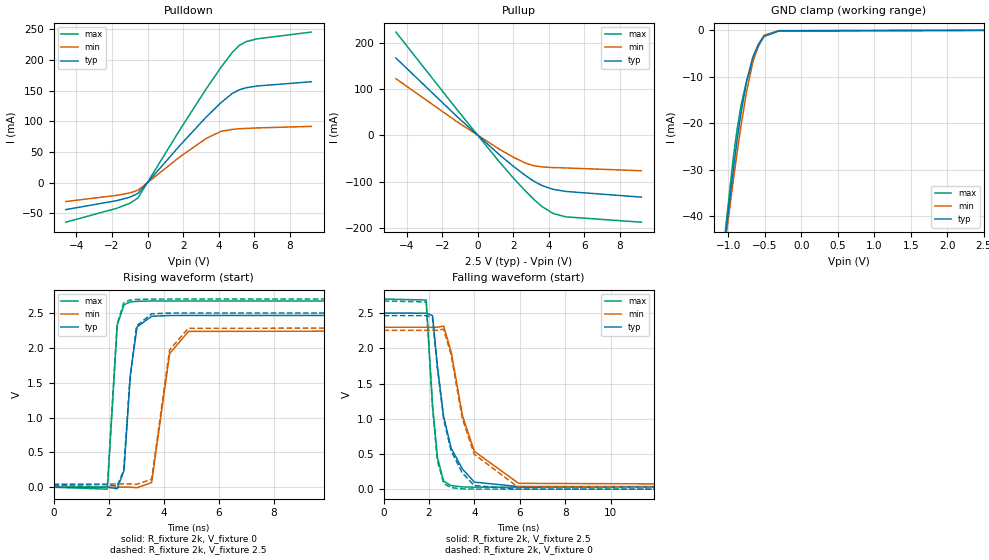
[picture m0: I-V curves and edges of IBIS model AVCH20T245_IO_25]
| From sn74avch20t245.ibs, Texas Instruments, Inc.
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[Model]   AVCH20T245_IO_25
Model_type  I/O
Vinl=0.7
Vinh=1.6
Enable   Active-Low
Vref =   0
Rref =   2000
Cref =   15p
Vmeas =   1.25
| variable   typ   min   max
C_comp   5.07pF   4.27pF   5.81pF
| C_pullup   4.25pF   3.23pF   5.64pF
| C_pulldown   4.37pF   3.82pF   4.81pF
| C_tri-state   5.07pF   4.27pF   5.81pF
[Temperature Range]   40   100   -40
| Ambient temperature   25   85   -40
[Voltage range]   2.5   2.3   2.7
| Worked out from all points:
|   slope of the pulldown table from 0 to 0.375 V, typ, clamps not added: 29.4 ohm
|   slope of the pullup table from 0 to 0.375 V, typ, clamps not added: 28.8 ohm
|   GND clamp passes 1 mA (typ) near -0.49 V on its own axis
|   rising waveform, R_fixture 2k, V_fixture 0: 20-80 % time 257ps typ, 389ps min, 181ps max; typ from 0 V to 2.46 V
|   falling waveform, R_fixture 2k, V_fixture 2.5: 20-80 % time 733ps typ, 1.04ns min, 343ps max; typ from 2.5 V to 0.036 V
|   rising waveform, R_fixture 2k, V_fixture 2.5: 20-80 % time 256ps typ, 385ps min, 180ps max; typ from 0.036 V to 2.5 V
|   falling waveform, R_fixture 2k, V_fixture 0: 20-80 % time 726ps typ, 1.04ns min, 335ps max; typ from 2.46 V to 0 V
[GND Clamp]
| AVCH20T245_IO_25
|   Voltage   I(typ)   I(min)   I(max)
-4.6V     -599.7mA   -548.2mA   -664.8mA
-1.105V   -53.1mA    -53.46mA   -52.72mA
-1.08V    -49.64mA   -50.32mA   -48.82mA
-930mV    -29.72mA   -32.1mA    -27.1mA
-880mV    -23.65mA   -26.37mA   -21.29mA
-825mV    -17.62mA   -20.4mA    -16.07mA
-750mV    -11.02mA   -13.17mA   -10.85mA
-665mV    -5.769mA   -6.898mA   -6.554mA
-590mV    -3.043mA   -3.142mA   -3.475mA
-510mV    -1.266mA   -1.045mA   -1.273mA
-305mV    -86.62uA   -60.85uA   -133.1uA
2.5V      1.213nA    2.545uA    -2.967uA
[Pulldown]
| AVCH20T245_IO_25
|   Voltage   I(typ)   I(min)   I(max)
-4.6V     -43.76mA   -30.71mA   -64.27mA
-1.715V   -29.08mA   -20.46mA   -41.45mA
-985mV    -23.44mA   -16.53mA   -33.24mA
-545mV    -17.41mA   -12.35mA   -24.86mA
1.85V     61.76mA    42.85mA    87.78mA
3.295V    106.9mA    72.08mA    152.8mA
4.12V     130.1mA    83.49mA    187.5mA
4.755V    145.2mA    86.77mA    211.8mA
5.15V     151.2mA    87.75mA    223.4mA
5.545V    154.6mA    88.42mA    229.7mA
6.15V     157.4mA    89.19mA    234.2mA
9.2V      164.4mA    91.67mA    245.2mA
[Pullup]
| AVCH20T245_IO_25
|   Voltage   I(typ)   I(min)   I(max)
-4.6V     167.2mA    122.6mA    223.3mA
-1.155V   40.55mA    29.45mA    55.44mA
1.195V    -40.71mA   -29.18mA   -56.05mA
2.025V    -67.14mA   -47.36mA   -92.77mA
2.695V    -86.73mA   -59.71mA   -120.4mA
3.12V     -97.9mA    -65.07mA   -136.7mA
3.615V    -108.1mA   -67.81mA   -153.5mA
4.245V    -116.2mA   -69.29mA   -168.4mA
4.95V     -120.8mA   -70.1mA    -175.7mA
9.2V      -133.1mA   -76.13mA   -187.2mA
[Ramp]
| AVCH20T245_IO_25
| variable   typ   min   max
dV/dt_r   1.49/2.65E-10   1.37/3.98E-10   1.62/1.93E-10
dV/dt_f   1.49/7.34E-10   1.37/1.04E-09   1.61/3.45E-10
R_load = 2k
[Rising Waveform]
| AVCH20T245_IO_25
R_fixture =   2k
C_fixture =   0
L_fixture =   0
V_fixture =   0
V_fixture_min = 0
V_fixture_max = 0
|   Time   V(typ)   V(min)   V(max)
0s        27.64nV    106.2nV    1.086nV
1.955ns   1.049mV    -45.02uV   -27.71mV
2.315ns   -22.31mV   -39.19uV   2.325V
2.56ns    240.7mV    1.682mV    2.619V
2.795ns   1.627V     1.405mV    2.658V
3.035ns   2.299V     -7.186mV   2.667V
3.565ns   2.453V     67.04mV    2.672V
4.22ns    2.464V     1.919V     2.672V
4.905ns   2.465V     2.236V     2.672V
34.99ns   2.465V     2.256V     2.672V
[Falling Waveform]
| AVCH20T245_IO_25
R_fixture =   2k
C_fixture =   0
L_fixture =   0
V_fixture =   2.5
V_fixture_min = 2.3
V_fixture_max = 2.7
|   Time   V(typ)   V(min)   V(max)
0s        2.5V       2.3V       2.7V
1.875ns   2.499V     2.3V       2.687V
2.155ns   2.466V     2.298V     1.192V
2.37ns    1.744V     2.301V     449.9mV
2.645ns   1.029V     2.316V     113.8mV
2.975ns   582.9mV    1.951V     50.11mV
3.475ns   285.4mV    1.042V     32.17mV
4ns       99.72mV    536.7mV    28.34mV
5.95ns    36.7mV     82.66mV    27.41mV
34.99ns   35.81mV    46.58mV    27.39mV
[Rising Waveform]
| AVCH20T245_IO_25
R_fixture =   2k
C_fixture =   0
L_fixture =   0
V_fixture =   2.5
V_fixture_min = 2.3
V_fixture_max = 2.7
|   Time   V(typ)   V(min)   V(max)
0s        35.81mV    46.58mV    27.38mV
1.955ns   36.86mV    46.54mV    -316.1uV
2.31ns    14.37mV    46.54mV    2.34V
2.55ns    245.1mV    48.2mV     2.644V
2.765ns   1.504V     48.3mV     2.684V
3.015ns   2.315V     40.4mV     2.695V
3.565ns   2.489V     115.9mV    2.699V
4.215ns   2.499V     1.969V     2.7V
4.895ns   2.5V       2.28V      2.7V
34.99ns   2.5V       2.3V       2.7V
[Falling Waveform]
| AVCH20T245_IO_25
R_fixture =   2k
C_fixture =   0
L_fixture =   0
V_fixture =   0
V_fixture_min = 0
V_fixture_max = 0
|   Time   V(typ)   V(min)   V(max)
0s        2.465V     2.256V     2.672V
1.875ns   2.464V     2.255V     2.66V
2.15ns    2.438V     2.254V     1.178V
2.365ns   1.728V     2.256V     410.7mV
2.645ns   996.2mV    2.272V     81.29mV
2.97ns    548.1mV    1.913V     21.73mV
3.47ns    228.7mV    1.002V     4.472mV
3.99ns    52.22mV    496.3mV    901uV
5.895ns   801.3uV    36.35mV    21.92uV
34.99ns   534.5nV    273.6nV    277.4nV
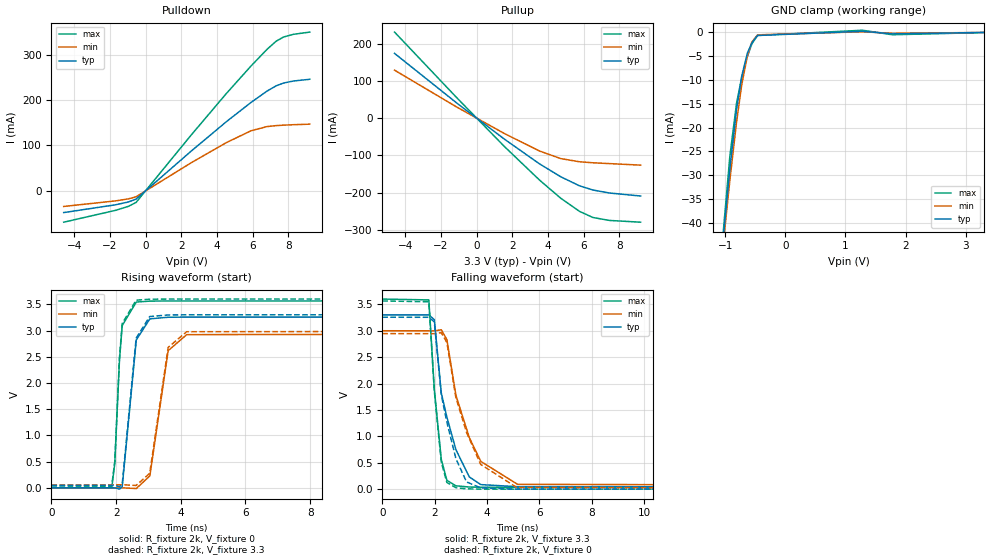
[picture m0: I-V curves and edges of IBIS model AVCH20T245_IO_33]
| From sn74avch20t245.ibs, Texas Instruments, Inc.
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[Model]   AVCH20T245_IO_33
Model_type  I/O
Vinl=0.8
Vinh=2.0
Enable   Active-Low
Vref =   0
Rref =   2000
Cref =   15p
Vmeas =   1.65
| variable   typ   min   max
C_comp   4.93pF   4.08pF   5.76pF
| C_pullup   3.99pF   3.01pF   5.24pF
| C_pulldown   4.20pF   3.64pF   4.73pF
| C_tri-state   4.93pF   4.08pF   5.76pF
[Temperature Range]   40   100   -40
| Ambient temperature   25   85   -40
[Voltage range]   3.3   3   3.6
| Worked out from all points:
|   slope of the pulldown table from 0 to 0.495 V, typ, clamps not added: 28.7 ohm
|   slope of the pullup table from 0 to 0.495 V, typ, clamps not added: 27.4 ohm
|   GND clamp passes 1 mA (typ) near -0.49 V on its own axis
|   rising waveform, R_fixture 2k, V_fixture 0: 20-80 % time 240ps typ, 358ps min, 166ps max; typ from 0 V to 3.26 V
|   falling waveform, R_fixture 2k, V_fixture 3.3: 20-80 % time 754ps typ, 1ns min, 333ps max; typ from 3.3 V to 0.046 V
|   rising waveform, R_fixture 2k, V_fixture 3.3: 20-80 % time 240ps typ, 356ps min, 165ps max; typ from 0.046 V to 3.3 V
|   falling waveform, R_fixture 2k, V_fixture 0: 20-80 % time 669ps typ, 1ns min, 328ps max; typ from 3.26 V to 0 V
[GND Clamp]
| AVCH20T245_IO_33
|   Voltage   I(typ)   I(min)   I(max)
-4.6V     -599.7mA   -548.3mA   -664.9mA
-1.12V    -55.23mA   -55.37mA   -55.14mA
-1.09V    -51.05mA   -51.59mA   -50.43mA
-920mV    -28.51mA   -30.95mA   -25.9mA
-810mV    -16.17mA   -18.87mA   -14.9mA
-725mV    -9.266mA   -11.11mA   -9.544mA
-630mV    -4.345mA   -4.957mA   -5.066mA
-555mV    -2.184mA   -2.008mA   -2.394mA
-460mV    -638.5uA   -501uA     -616.7uA
1.285V    253.4uA    145.8uA    464.3uA
1.78V     -297.7uA   -185uA     -481uA
3.3V      1.647nA    4.592uA    -26.77uA
[Pulldown]
| AVCH20T245_IO_33
|   Voltage   I(typ)   I(min)   I(max)
-4.6V     -47.48mA   -33.99mA   -68.59mA
-1.68V    -30.25mA   -21.7mA    -42.42mA
-975mV    -24.15mA   -17.32mA   -33.81mA
-545mV    -17.86mA   -12.84mA   -25.24mA
2.545V    87.52mA    61.96mA    122.8mA
4.505V    151.8mA    106mA      213.5mA
5.905V    194.7mA    132.4mA    274.8mA
6.805V    219.6mA    141.6mA    311.5mA
7.315V    231.2mA    143.7mA    329.3mA
7.73V     237.3mA    144.7mA    338.5mA
8.28V     241.7mA    145.7mA    344.4mA
9.2V      245.6mA    146.9mA    349.3mA
[Pullup]
| AVCH20T245_IO_33
|   Voltage   I(typ)   I(min)   I(max)
-4.6V     174.2mA    129.1mA    231.4mA
-1.105V   40.58mA    29.86mA    54.82mA
1.575V    -56.66mA   -41.45mA   -76.65mA
3.53V     -122.6mA   -88.07mA   -166.1mA
4.725V    -157.4mA   -108.5mA   -215.1mA
5.775V    -181.6mA   -117mA     -250.3mA
6.525V    -192.9mA   -119.7mA   -266.7mA
7.455V    -200.9mA   -121.9mA   -274.6mA
9.2V      -209mA     -126mA     -279.3mA
[Ramp]
| AVCH20T245_IO_33
| variable   typ   min   max
dV/dt_r   1.97/2.44E-10   1.78/3.62E-10   2.16/1.71E-10
dV/dt_f   1.96/7.54E-10   1.78/1.01E-09   2.14/3.34E-10
R_load = 2k
[Rising Waveform]
| AVCH20T245_IO_33
R_fixture =   2k
C_fixture =   0
L_fixture =   0
V_fixture =   0
V_fixture_min = 0
V_fixture_max = 0
|   Time   V(typ)   V(min)   V(max)
0s        37.78nV    120nV      1.948nV
1.865ns   1.869mV    -41.13uV   -5.4mV
1.96ns    -162uV     4.029uV    469.2mV
2.105ns   -24.9mV    325.1uV    2.438V
2.19ns    25.66mV    863.2uV    3.095V
2.625ns   2.821V     -13.07mV   3.543V
3.045ns   3.223V     228.9mV    3.561V
3.61ns    3.253V     2.616V     3.564V
4.185ns   3.256V     2.922V     3.564V
34.99ns   3.256V     2.946V     3.564V
[Falling Waveform]
| AVCH20T245_IO_33
R_fixture =   2k
C_fixture =   0
L_fixture =   0
V_fixture =   3.3
V_fixture_min = 3
V_fixture_max = 3.6
|   Time   V(typ)   V(min)   V(max)
0s        3.3V       3V         3.6V
1.78ns    3.3V       2.999V     3.584V
1.99ns    3.21V      2.998V     1.886V
2.255ns   1.823V     3.018V     566.3mV
2.47ns    1.363V     2.832V     167.6mV
2.815ns   746.6mV    1.777V     63.34mV
3.325ns   232.5mV    978.3mV    40.41mV
3.765ns   86.36mV    525.6mV    37.03mV
5.17ns    47.12mV    91.58mV    36mV
34.99ns   46.09mV    58.43mV    35.95mV
[Rising Waveform]
| AVCH20T245_IO_33
R_fixture =   2k
C_fixture =   0
L_fixture =   0
V_fixture =   3.3
V_fixture_min = 3
V_fixture_max = 3.6
|   Time   V(typ)   V(min)   V(max)
0s        46.09mV    58.43mV    35.95mV
1.865ns   47.95mV    58.39mV    30.52mV
1.96ns    45.9mV     58.44mV    505.8mV
2.105ns   21.1mV     58.76mV    2.477V
2.19ns    71.98mV    59.3mV     3.134V
2.62ns    2.854V     45.78mV    3.579V
3.04ns    3.267V     277.1mV    3.597V
3.61ns    3.297V     2.678V     3.6V
4.18ns    3.3V       2.977V     3.6V
34.99ns   3.3V       3V         3.6V
[Falling Waveform]
| AVCH20T245_IO_33
R_fixture =   2k
C_fixture =   0
L_fixture =   0
V_fixture =   0
V_fixture_min = 0
V_fixture_max = 0
|   Time   V(typ)   V(min)   V(max)
0s        3.256V     2.946V     3.564V
1.78ns    3.255V     2.945V     3.549V
1.99ns    3.166V     2.943V     1.858V
2.255ns   1.787V     2.964V     512.2mV
2.47ns    1.267V     2.777V     127.1mV
2.815ns   576.6mV    1.73V      26.61mV
3.22ns    137.3mV    1.076V     6.147mV
3.76ns    24.03mV    469.5mV    1.051mV
5.135ns   642.9uV    33.27mV    41.94uV
34.99ns   603.5nV    641.4nV    268nV
